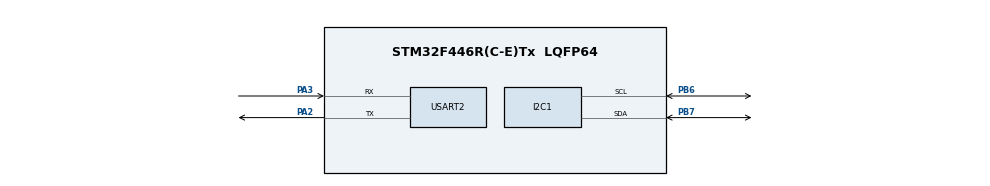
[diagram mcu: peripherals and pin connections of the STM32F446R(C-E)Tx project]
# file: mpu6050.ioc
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Mcu.Family=STM32F4
Mcu.Name=STM32F446R(C-E)Tx
Mcu.Package=LQFP64
NVIC.PriorityGroup=NVIC_PRIORITYGROUP_4
PA2.Mode=Asynchronous
PA2.Signal=USART2_TX
PA3.Mode=Asynchronous
PA3.Signal=USART2_RX
PB6.Mode=I2C
PB6.Signal=I2C1_SCL
PB7.Mode=I2C
PB7.Signal=I2C1_SDA
ProjectManager.HeapSize=0x200
ProjectManager.StackSize=0x400
ProjectManager.TargetToolchain=STM32CubeIDE
RCC.CortexFreq_Value=16000000
RCC.USBFreq_Value=96000000
RCC.VCOOutputFreq_Value=192000000
USART2.VirtualMode=VM_ASYNC
board=custom

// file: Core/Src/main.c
/* USER CODE BEGIN Header */
/**
  ******************************************************************************
  * @file           : main.c
  * @brief          : Main program body
  ******************************************************************************
  * @attention
  *
  * Copyright (c) 2024 STMicroelectronics.
  * All rights reserved.
  *
  * This software is licensed under terms that can be found in the LICENSE file
  * in the root directory of this software component.
  * If no LICENSE file comes with this software, it is provided AS-IS.
  *
  ******************************************************************************
  */
/* USER CODE END Header */
#include "main.h"

/* USER CODE BEGIN Includes */
#include <stdio.h>
#include <stdlib.h>
#include <string.h>
#include "mpu6050.h"
/* USER CODE END Includes */

I2C_HandleTypeDef hi2c1;

UART_HandleTypeDef huart2;

void SystemClock_Config(void);
static void MX_GPIO_Init(void);
static void MX_I2C1_Init(void);
static void MX_USART2_UART_Init(void);

int main(void)
{

  /* MCU Configuration--------------------------------------------------------*/

  /* Reset of all peripherals, Initializes the Flash interface and the Systick. */
  HAL_Init();

  /* Configure the system clock */
  SystemClock_Config();

  /* Initialize all configured peripherals */
  MX_GPIO_Init();
  MX_I2C1_Init();
  MX_USART2_UART_Init();
  /* USER CODE BEGIN 2 */
  mpu6050_init();
  /* USER CODE END 2 */

  /* Infinite loop */
  /* USER CODE BEGIN WHILE */
  while (1)
  {
	mpu6050_read();
	HAL_Delay(100);
    /* USER CODE END WHILE */

  }
}

void SystemClock_Config(void)
{
  RCC_OscInitTypeDef RCC_OscInitStruct = {0};
  RCC_ClkInitTypeDef RCC_ClkInitStruct = {0};

  /** Configure the main internal regulator output voltage
  */
  __HAL_RCC_PWR_CLK_ENABLE();
  __HAL_PWR_VOLTAGESCALING_CONFIG(PWR_REGULATOR_VOLTAGE_SCALE3);

  /** Initializes the RCC Oscillators according to the specified parameters
  * in the RCC_OscInitTypeDef structure.
  */
  RCC_OscInitStruct.OscillatorType = RCC_OSCILLATORTYPE_HSI;
  RCC_OscInitStruct.HSIState = RCC_HSI_ON;
  RCC_OscInitStruct.HSICalibrationValue = RCC_HSICALIBRATION_DEFAULT;
  RCC_OscInitStruct.PLL.PLLState = RCC_PLL_ON;
  RCC_OscInitStruct.PLL.PLLSource = RCC_PLLSOURCE_HSI;
  RCC_OscInitStruct.PLL.PLLM = 8;
  RCC_OscInitStruct.PLL.PLLN = 80;
  RCC_OscInitStruct.PLL.PLLP = RCC_PLLP_DIV2;
  RCC_OscInitStruct.PLL.PLLQ = 2;
  RCC_OscInitStruct.PLL.PLLR = 2;
  if (HAL_RCC_OscConfig(&RCC_OscInitStruct) != HAL_OK)
  {
    Error_Handler();
  }

  /** Initializes the CPU, AHB and APB buses clocks
  */
  RCC_ClkInitStruct.ClockType = RCC_CLOCKTYPE_HCLK|RCC_CLOCKTYPE_SYSCLK
                              |RCC_CLOCKTYPE_PCLK1|RCC_CLOCKTYPE_PCLK2;
  RCC_ClkInitStruct.SYSCLKSource = RCC_SYSCLKSOURCE_PLLCLK;
  RCC_ClkInitStruct.AHBCLKDivider = RCC_SYSCLK_DIV1;
  RCC_ClkInitStruct.APB1CLKDivider = RCC_HCLK_DIV2;
  RCC_ClkInitStruct.APB2CLKDivider = RCC_HCLK_DIV1;

  if (HAL_RCC_ClockConfig(&RCC_ClkInitStruct, FLASH_LATENCY_2) != HAL_OK)
  {
    Error_Handler();
  }
}

static void MX_I2C1_Init(void)
{

  hi2c1.Instance = I2C1;
  hi2c1.Init.ClockSpeed = 100000;
  hi2c1.Init.DutyCycle = I2C_DUTYCYCLE_2;
  hi2c1.Init.OwnAddress1 = 0;
  hi2c1.Init.AddressingMode = I2C_ADDRESSINGMODE_7BIT;
  hi2c1.Init.DualAddressMode = I2C_DUALADDRESS_DISABLE;
  hi2c1.Init.OwnAddress2 = 0;
  hi2c1.Init.GeneralCallMode = I2C_GENERALCALL_DISABLE;
  hi2c1.Init.NoStretchMode = I2C_NOSTRETCH_DISABLE;
  if (HAL_I2C_Init(&hi2c1) != HAL_OK)
  {
    Error_Handler();
  }

}

static void MX_USART2_UART_Init(void)
{

  huart2.Instance = USART2;
  huart2.Init.BaudRate = 115200;
  huart2.Init.WordLength = UART_WORDLENGTH_8B;
  huart2.Init.StopBits = UART_STOPBITS_1;
  huart2.Init.Parity = UART_PARITY_NONE;
  huart2.Init.Mode = UART_MODE_TX_RX;
  huart2.Init.HwFlowCtl = UART_HWCONTROL_NONE;
  huart2.Init.OverSampling = UART_OVERSAMPLING_16;
  if (HAL_UART_Init(&huart2) != HAL_OK)
  {
    Error_Handler();
  }

}

static void MX_GPIO_Init(void)
{

  /* GPIO Ports Clock Enable */
  __HAL_RCC_GPIOA_CLK_ENABLE();
  __HAL_RCC_GPIOB_CLK_ENABLE();

}

/* USER CODE BEGIN 4 */
int _write(int file, char *ptr, int len)
{
  (void)file;
  int DataIdx;

  for (DataIdx = 0; DataIdx < len; DataIdx++)
  {
    ITM_SendChar(*ptr++);
  }
  return len;
}
/* USER CODE END 4 */

void Error_Handler(void)
{
  __disable_irq();
  while (1)
  {
  }
}
